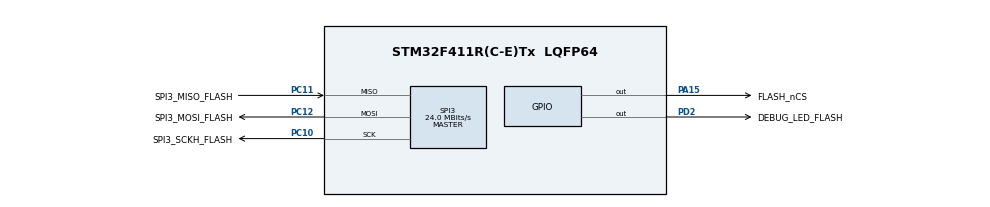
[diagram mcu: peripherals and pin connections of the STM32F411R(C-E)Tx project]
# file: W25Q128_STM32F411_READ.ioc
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Mcu.Family=STM32F4
Mcu.Name=STM32F411R(C-E)Tx
Mcu.Package=LQFP64
NVIC.PriorityGroup=NVIC_PRIORITYGROUP_4
PA15.GPIO_Label=FLASH_nCS
PA15.GPIO_Speed=GPIO_SPEED_FREQ_HIGH
PA15.PinState=GPIO_PIN_SET
PA15.Signal=GPIO_Output
PC10.GPIO_Label=SPI3_SCKH_FLASH
PC10.Mode=Full_Duplex_Master
PC10.Signal=SPI3_SCK
PC11.GPIO_Label=SPI3_MISO_FLASH
PC11.Mode=Full_Duplex_Master
PC11.Signal=SPI3_MISO
PC12.GPIO_Label=SPI3_MOSI_FLASH
PC12.Mode=Full_Duplex_Master
PC12.Signal=SPI3_MOSI
PD2.GPIO_Label=DEBUG_LED_FLASH
PD2.GPIO_Speed=GPIO_SPEED_FREQ_HIGH
PD2.PinState=GPIO_PIN_RESET
PD2.Signal=GPIO_Output
ProjectManager.HeapSize=0x200
ProjectManager.StackSize=0x400
ProjectManager.TargetToolchain=STM32CubeIDE
RCC.48MHZClocksFreq_Value=48000000
RCC.AHBFreq_Value=96000000
RCC.APB1CLKDivider=RCC_HCLK_DIV2
RCC.APB1Freq_Value=48000000
RCC.APB1TimFreq_Value=96000000
RCC.APB2Freq_Value=96000000
RCC.APB2TimFreq_Value=96000000
RCC.CortexFreq_Value=96000000
RCC.HCLKFreq_Value=96000000
RCC.HSE_VALUE=25000000
RCC.HSI_VALUE=16000000
RCC.LSE_VALUE=32768
RCC.PLLM=8
RCC.PLLN=96
RCC.SYSCLKFreq_VALUE=96000000
RCC.SYSCLKSource=RCC_SYSCLKSOURCE_PLLCLK
RCC.VCOOutputFreq_Value=192000000
SPI3.CalculateBaudRate=24.0 MBits/s
SPI3.Direction=SPI_DIRECTION_2LINES
SPI3.Mode=SPI_MODE_MASTER
SPI3.VirtualType=VM_MASTER
board=custom

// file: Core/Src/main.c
/* USER CODE BEGIN Header */
/**
  ******************************************************************************
  * @file           : main.c
  * @brief          : Main program body
  ******************************************************************************
  * @attention
  *
  * Copyright (c) 2024 STMicroelectronics.
  * All rights reserved.
  *
  * This software is licensed under terms that can be found in the LICENSE file
  * in the root directory of this software component.
  * If no LICENSE file comes with this software, it is provided AS-IS.
  *
  ******************************************************************************
  */
/* USER CODE END Header */
#include "main.h"
#include "spi.h"
#include "gpio.h"

void SystemClock_Config(void);

int main(void)
{

  /* MCU Configuration--------------------------------------------------------*/

  /* Reset of all peripherals, Initializes the Flash interface and the Systick. */
  HAL_Init();

  /* Configure the system clock */
  SystemClock_Config();

  /* Initialize all configured peripherals */
  MX_GPIO_Init();
  MX_SPI3_Init();

  /* Infinite loop */
  while (1)
  {

  }
}

void SystemClock_Config(void)
{
  RCC_OscInitTypeDef RCC_OscInitStruct = {0};
  RCC_ClkInitTypeDef RCC_ClkInitStruct = {0};

  /** Configure the main internal regulator output voltage
  */
  __HAL_RCC_PWR_CLK_ENABLE();
  __HAL_PWR_VOLTAGESCALING_CONFIG(PWR_REGULATOR_VOLTAGE_SCALE1);

  /** Initializes the RCC Oscillators according to the specified parameters
  * in the RCC_OscInitTypeDef structure.
  */
  RCC_OscInitStruct.OscillatorType = RCC_OSCILLATORTYPE_HSE;
  RCC_OscInitStruct.HSEState = RCC_HSE_ON;
  //RCC_OscInitStruct.HSICalibrationValue = RCC_HSICALIBRATION_DEFAULT;
  RCC_OscInitStruct.PLL.PLLState = RCC_PLL_ON;
  RCC_OscInitStruct.PLL.PLLSource = RCC_PLLSOURCE_HSE;
  RCC_OscInitStruct.PLL.PLLM = 8;
  RCC_OscInitStruct.PLL.PLLN = 96;
  RCC_OscInitStruct.PLL.PLLP = RCC_PLLP_DIV2;
  RCC_OscInitStruct.PLL.PLLQ = 4;
  if (HAL_RCC_OscConfig(&RCC_OscInitStruct) != HAL_OK)
  {
    Error_Handler();
  }

  /** Initializes the CPU, AHB and APB buses clocks
  */
  RCC_ClkInitStruct.ClockType = RCC_CLOCKTYPE_HCLK|RCC_CLOCKTYPE_SYSCLK
                              |RCC_CLOCKTYPE_PCLK1|RCC_CLOCKTYPE_PCLK2;
  RCC_ClkInitStruct.SYSCLKSource = RCC_SYSCLKSOURCE_PLLCLK;
  RCC_ClkInitStruct.AHBCLKDivider = RCC_SYSCLK_DIV1;
  RCC_ClkInitStruct.APB1CLKDivider = RCC_HCLK_DIV2;
  RCC_ClkInitStruct.APB2CLKDivider = RCC_HCLK_DIV1;

  if (HAL_RCC_ClockConfig(&RCC_ClkInitStruct, FLASH_LATENCY_3) != HAL_OK)
  {
    Error_Handler();
  }
}

void Error_Handler(void)
{
  __disable_irq();
  while (1)
  {
  }
}
